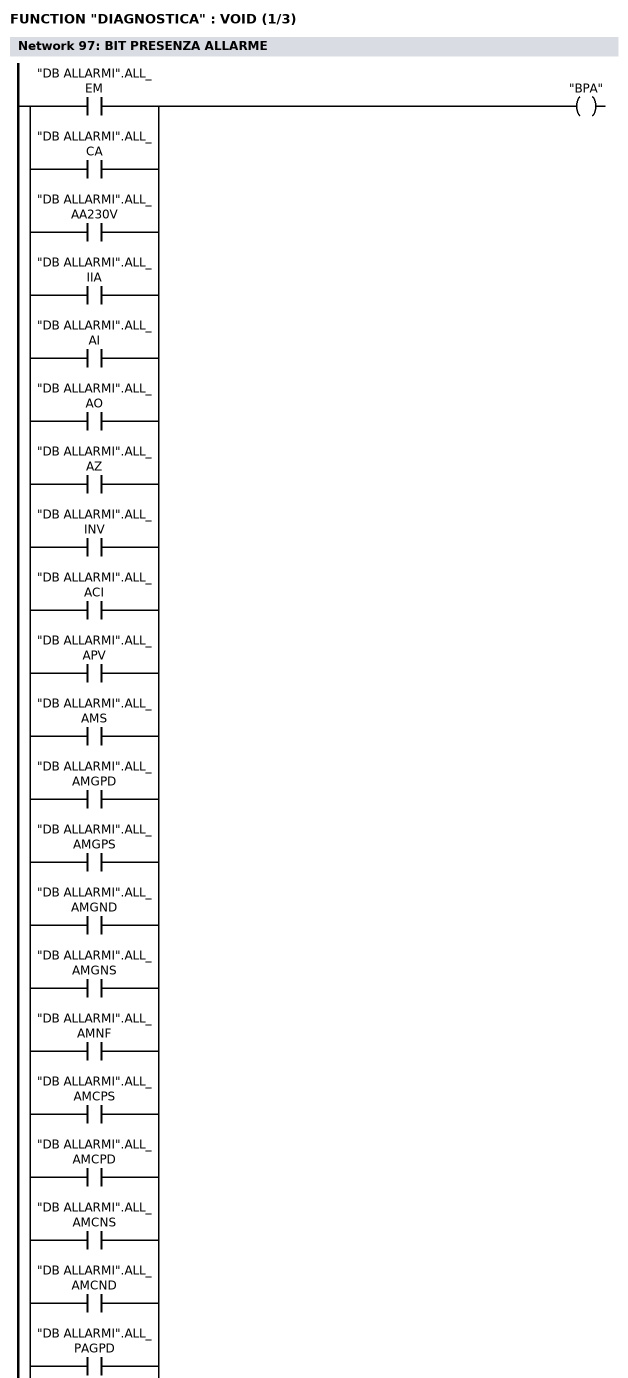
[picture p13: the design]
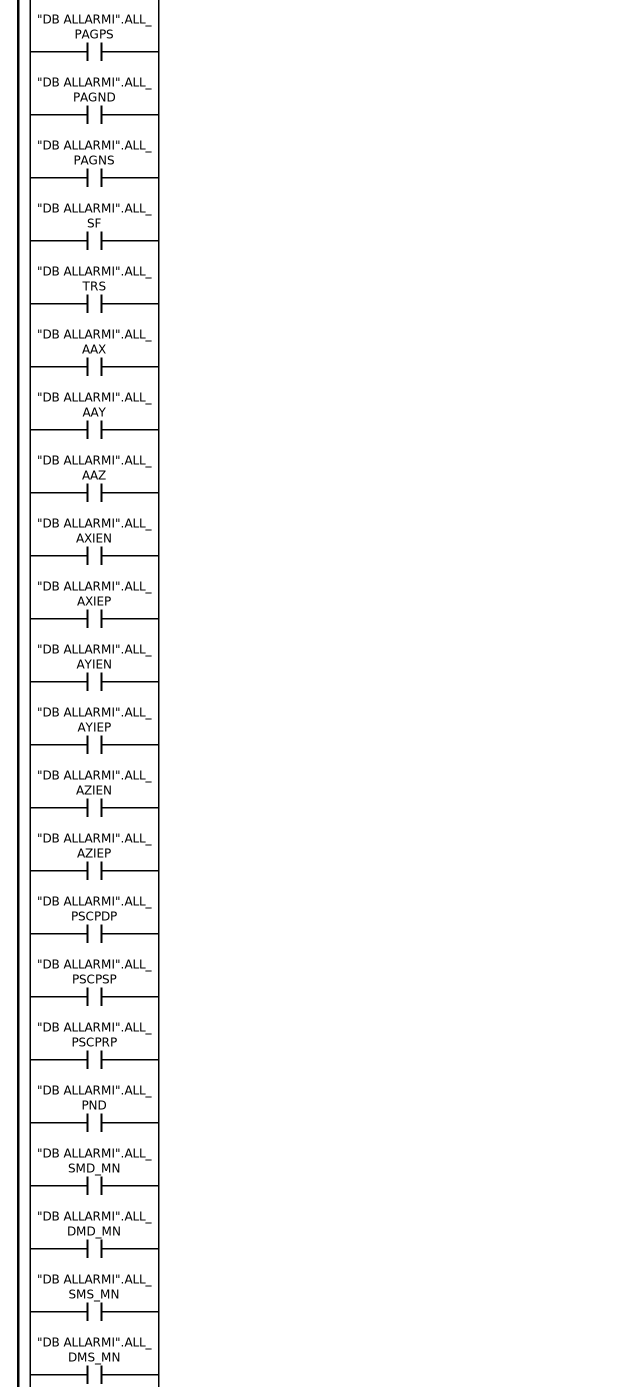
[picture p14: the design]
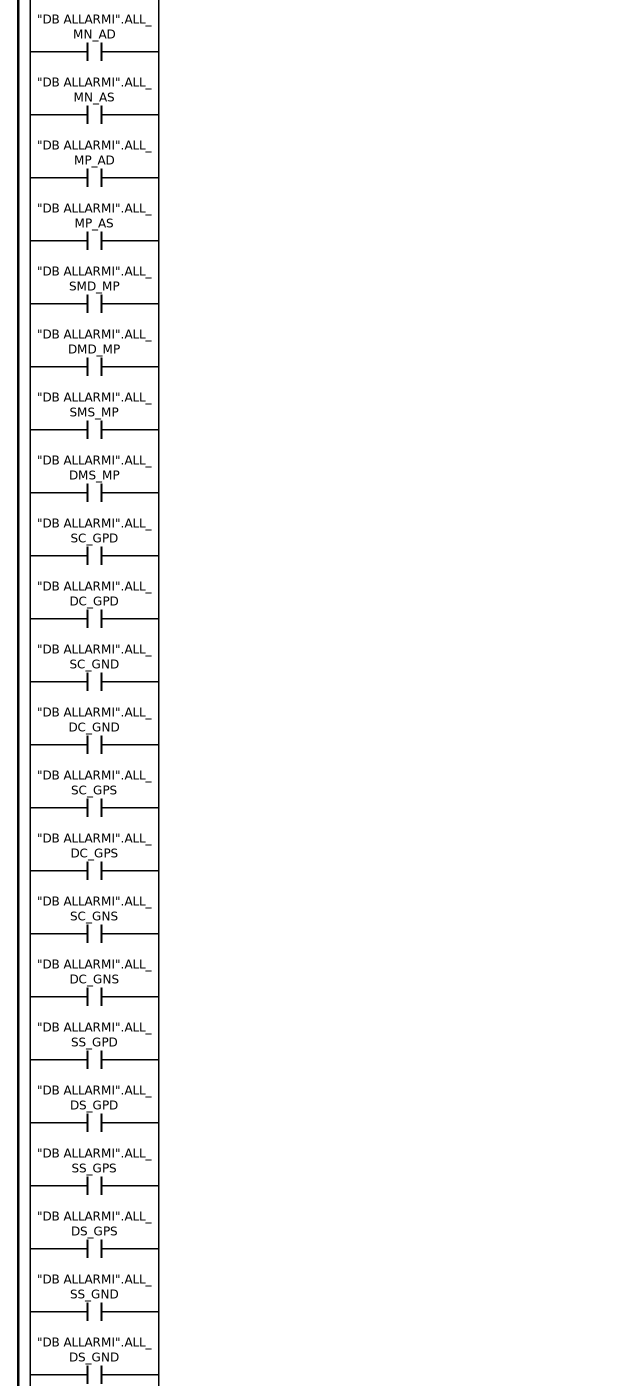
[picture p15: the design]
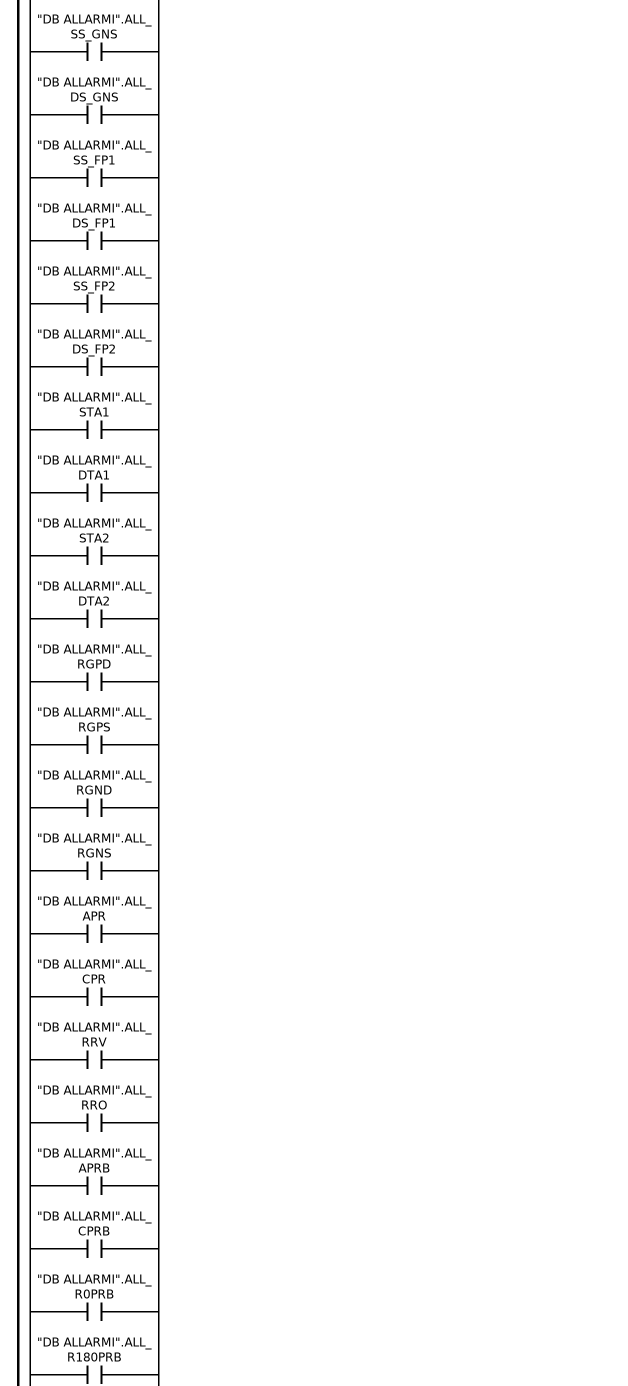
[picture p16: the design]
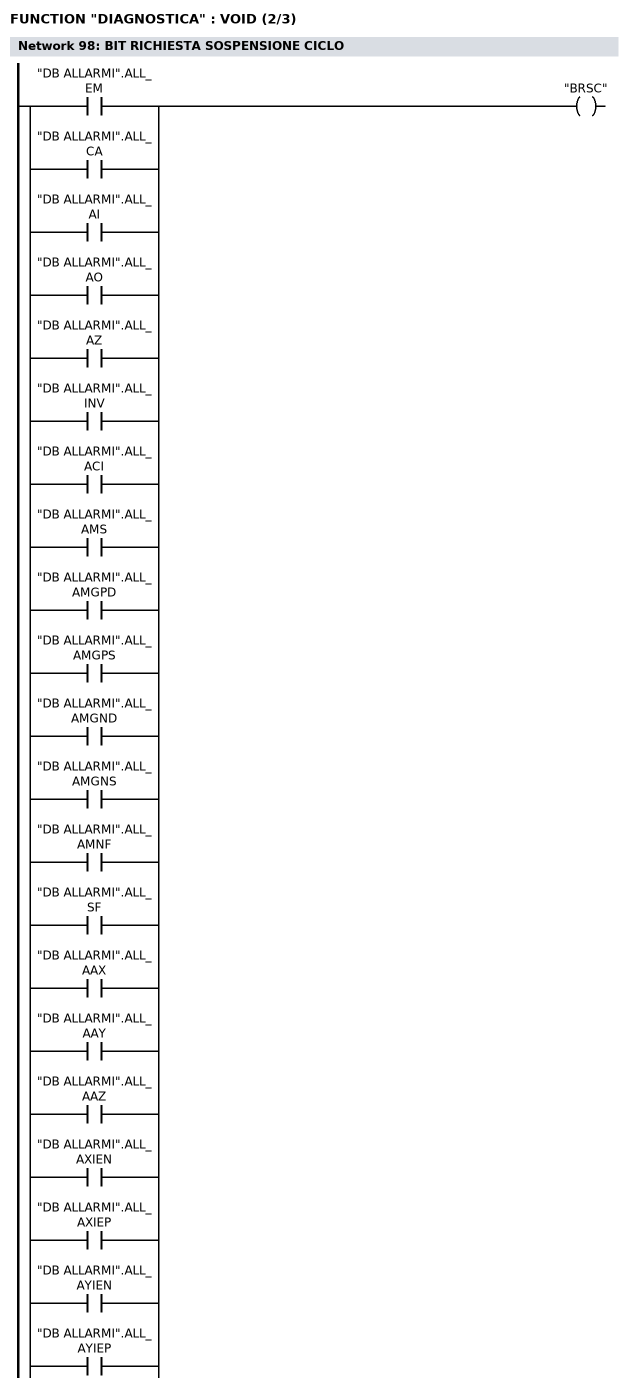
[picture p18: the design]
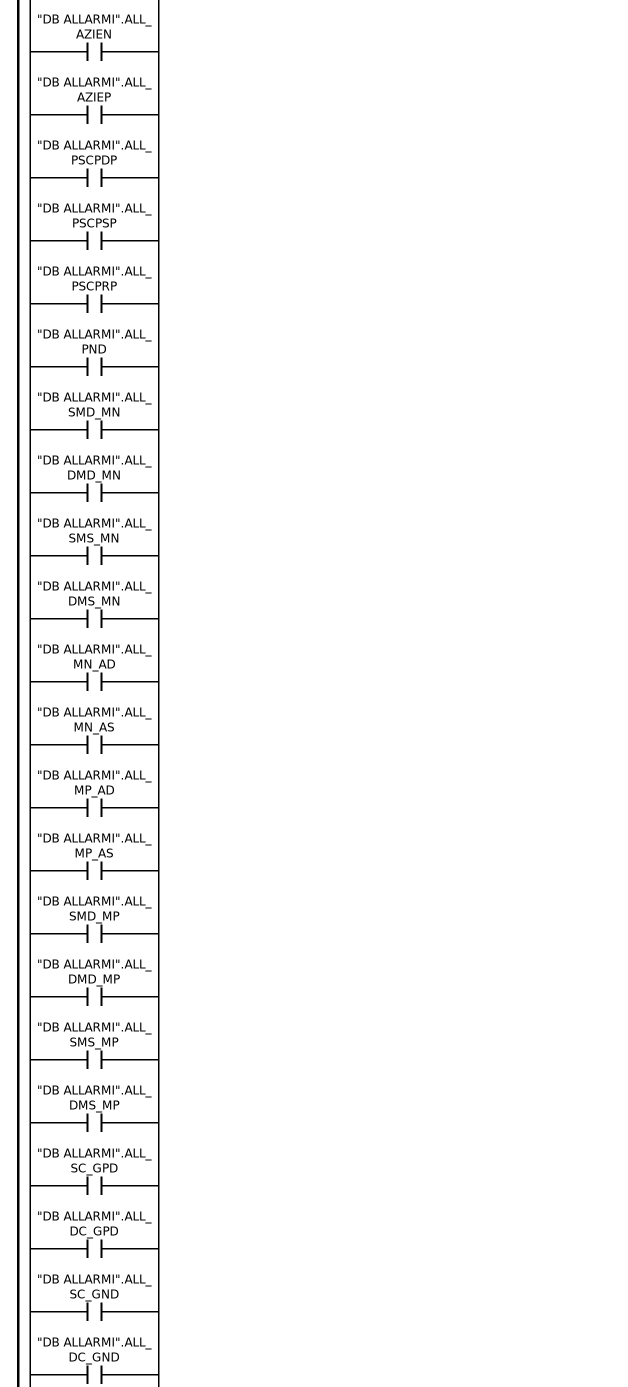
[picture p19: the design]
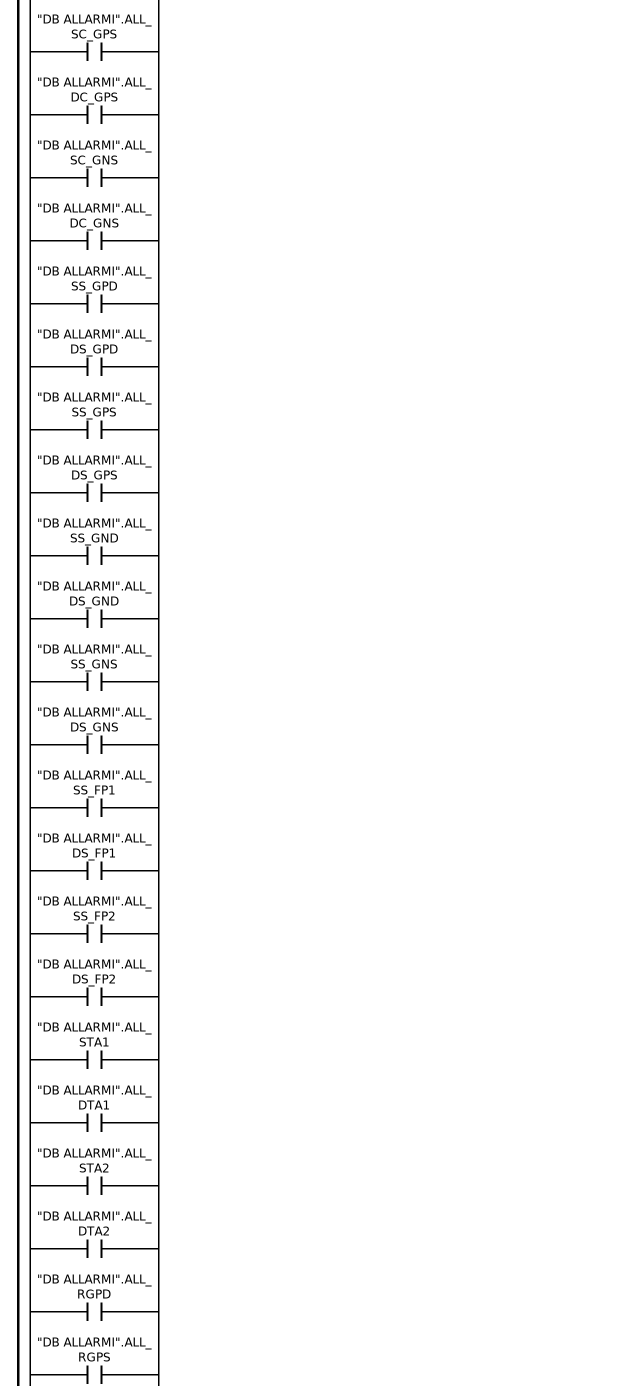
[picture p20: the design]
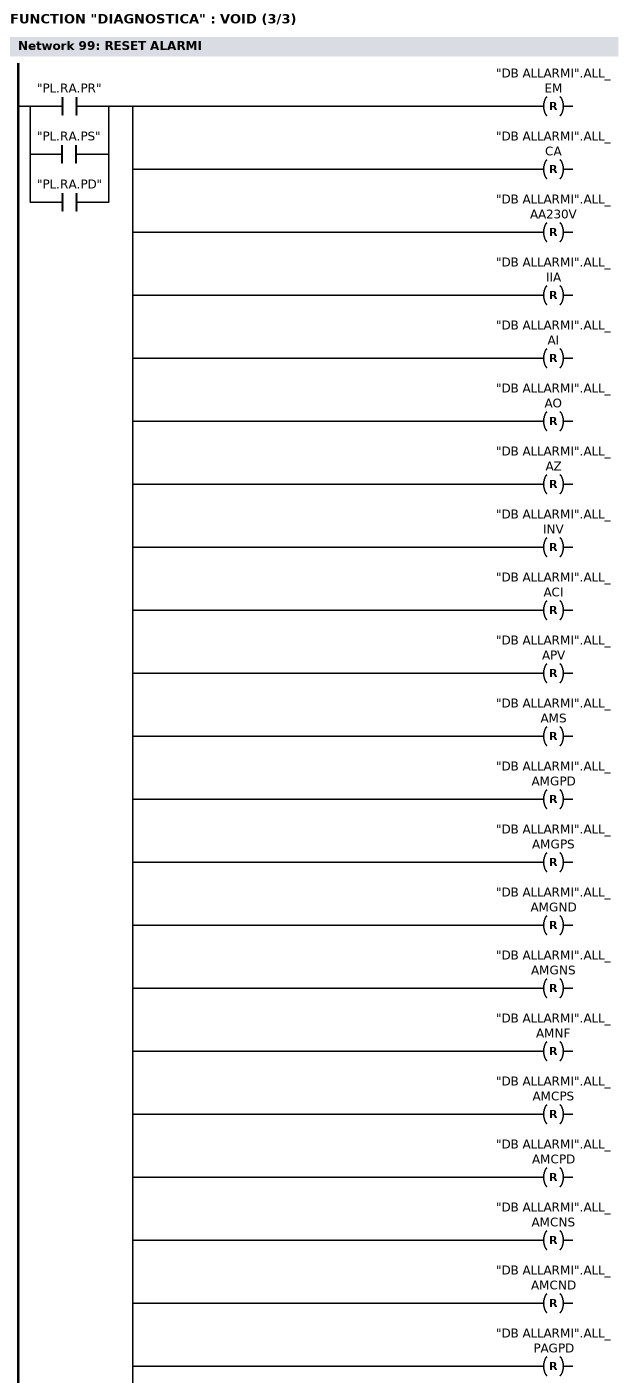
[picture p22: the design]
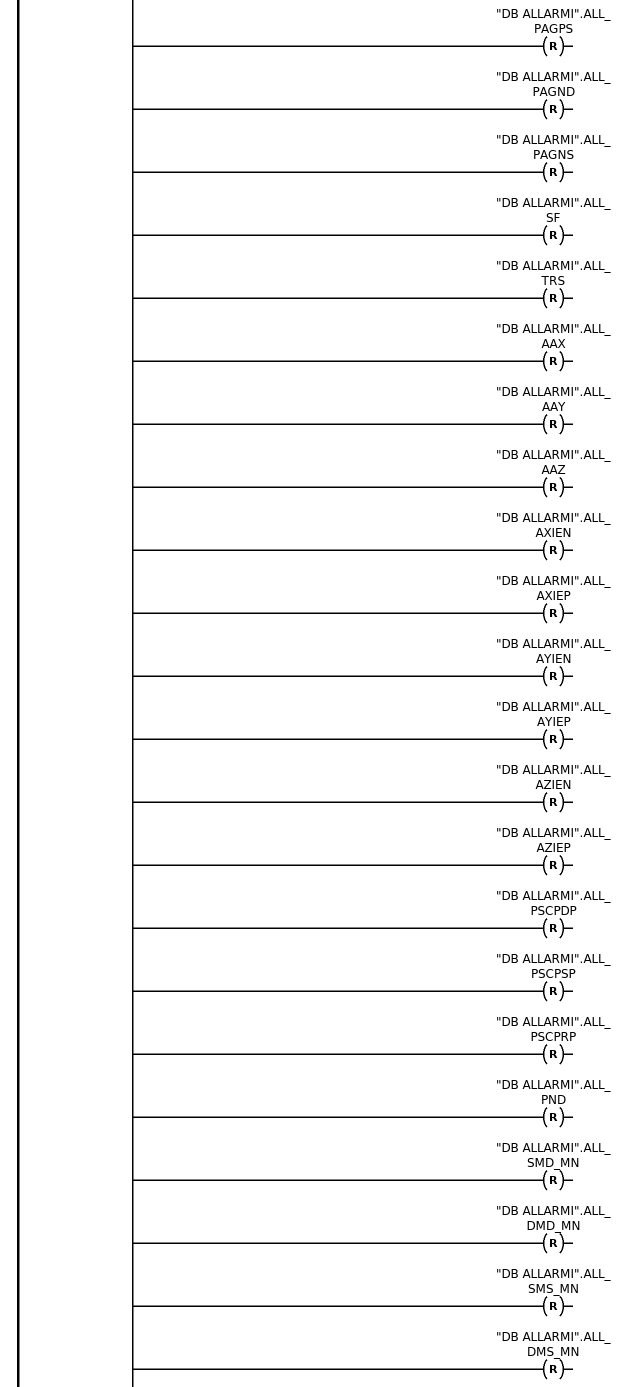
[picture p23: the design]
FUNCTION "DIAGNOSTICA" : VOID
TITLE =DIAGNOSTICA
VERSION : 0.1

BEGIN
NETWORK
TITLE =EMERGENZA

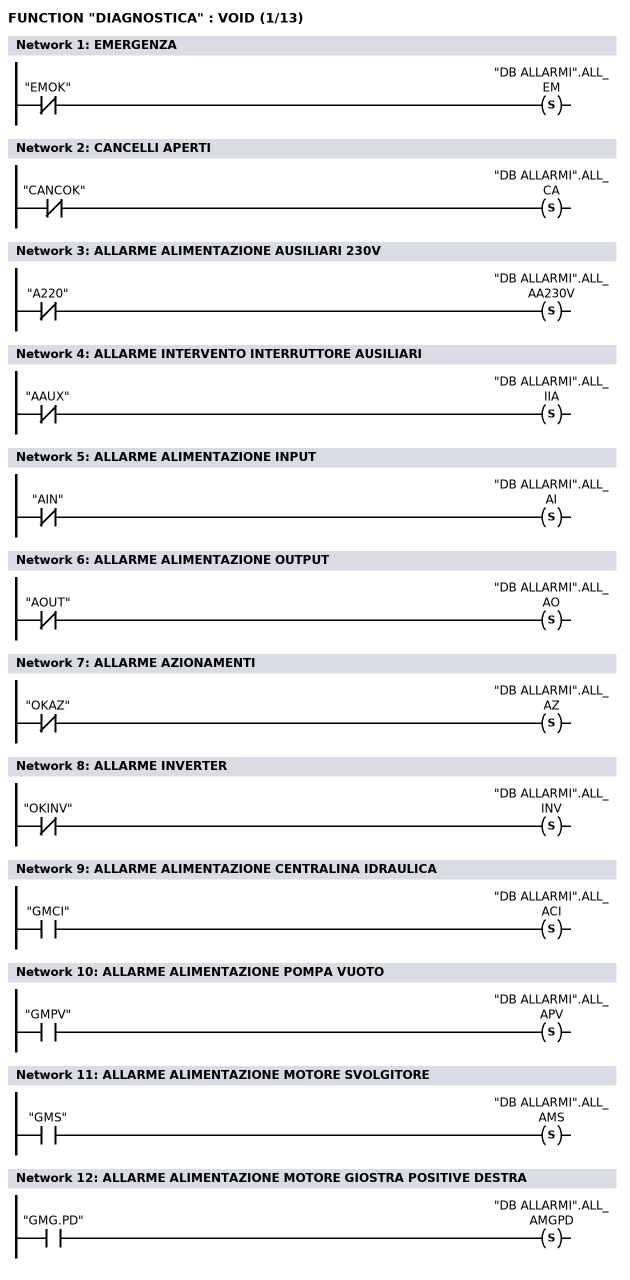
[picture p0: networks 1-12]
      UN    "EMOK";
      S     "DB ALLARMI".ALL_EM;

NETWORK
TITLE =CANCELLI APERTI

      UN    "CANCOK";
      S     "DB ALLARMI".ALL_CA;

NETWORK
TITLE =ALLARME ALIMENTAZIONE AUSILIARI 230V

      UN    "A220";
      S     "DB ALLARMI".ALL_AA230V;

NETWORK
TITLE =ALLARME INTERVENTO INTERRUTTORE AUSILIARI

      UN    "AAUX";
      S     "DB ALLARMI".ALL_IIA;

NETWORK
TITLE =ALLARME ALIMENTAZIONE INPUT

      UN    "AIN";
      S     "DB ALLARMI".ALL_AI;

NETWORK
TITLE =ALLARME ALIMENTAZIONE OUTPUT

      UN    "AOUT";
      S     "DB ALLARMI".ALL_AO;

NETWORK
TITLE =ALLARME AZIONAMENTI

      UN    "OKAZ";
      S     "DB ALLARMI".ALL_AZ;

NETWORK
TITLE =ALLARME INVERTER

      UN    "OKINV";
      S     "DB ALLARMI".ALL_INV;

NETWORK
TITLE =ALLARME ALIMENTAZIONE CENTRALINA IDRAULICA

      U     "GMCI";
      S     "DB ALLARMI".ALL_ACI;

NETWORK
TITLE =ALLARME ALIMENTAZIONE POMPA VUOTO

      U     "GMPV";
      S     "DB ALLARMI".ALL_APV;

NETWORK
TITLE =ALLARME ALIMENTAZIONE MOTORE SVOLGITORE

      U     "GMS";
      S     "DB ALLARMI".ALL_AMS;

NETWORK
TITLE =ALLARME ALIMENTAZIONE MOTORE GIOSTRA POSITIVE DESTRA

      U     "GMG.PD";
      S     "DB ALLARMI".ALL_AMGPD;

NETWORK
TITLE =ALLARME ALIMENTAZIONE MOTORE GIOSTRA POSITIVE SINISTRA

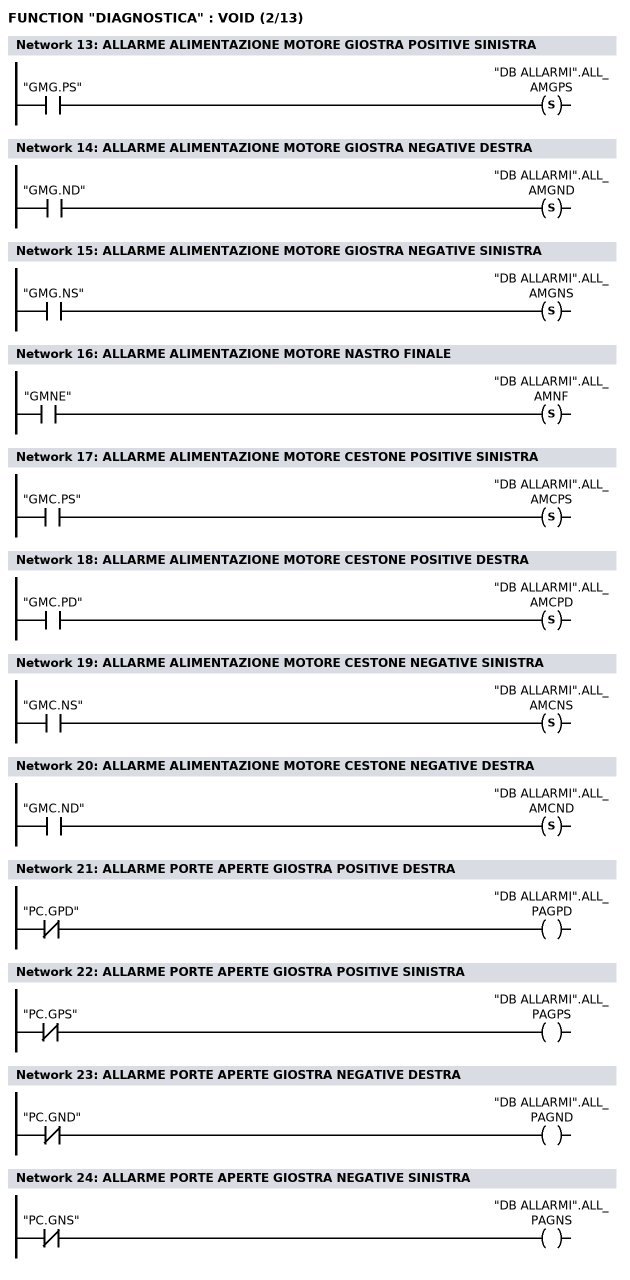
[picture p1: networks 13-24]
      U     "GMG.PS";
      S     "DB ALLARMI".ALL_AMGPS;

NETWORK
TITLE =ALLARME ALIMENTAZIONE MOTORE GIOSTRA NEGATIVE DESTRA

      U     "GMG.ND";
      S     "DB ALLARMI".ALL_AMGND;

NETWORK
TITLE =ALLARME ALIMENTAZIONE MOTORE GIOSTRA NEGATIVE SINISTRA

      U     "GMG.NS";
      S     "DB ALLARMI".ALL_AMGNS;

NETWORK
TITLE =ALLARME ALIMENTAZIONE MOTORE NASTRO FINALE

      U     "GMNE";
      S     "DB ALLARMI".ALL_AMNF;

NETWORK
TITLE =ALLARME ALIMENTAZIONE MOTORE CESTONE POSITIVE SINISTRA

      U     "GMC.PS";
      S     "DB ALLARMI".ALL_AMCPS;

NETWORK
TITLE =ALLARME ALIMENTAZIONE MOTORE CESTONE POSITIVE DESTRA

      U     "GMC.PD";
      S     "DB ALLARMI".ALL_AMCPD;

NETWORK
TITLE =ALLARME ALIMENTAZIONE MOTORE CESTONE NEGATIVE SINISTRA

      U     "GMC.NS";
      S     "DB ALLARMI".ALL_AMCNS;

NETWORK
TITLE =ALLARME ALIMENTAZIONE MOTORE CESTONE NEGATIVE DESTRA

      U     "GMC.ND";
      S     "DB ALLARMI".ALL_AMCND;

NETWORK
TITLE =ALLARME PORTE APERTE GIOSTRA POSITIVE DESTRA

      UN    "PC.GPD";
      =     "DB ALLARMI".ALL_PAGPD;

NETWORK
TITLE =ALLARME PORTE APERTE GIOSTRA POSITIVE SINISTRA

      UN    "PC.GPS";
      =     "DB ALLARMI".ALL_PAGPS;

NETWORK
TITLE =ALLARME PORTE APERTE GIOSTRA NEGATIVE DESTRA

      UN    "PC.GND";
      =     "DB ALLARMI".ALL_PAGND;

NETWORK
TITLE =ALLARME PORTE APERTE GIOSTRA NEGATIVE SINISTRA

      UN    "PC.GNS";
      =     "DB ALLARMI".ALL_PAGNS;

NETWORK
TITLE =ALLARME SEPARATORE FINITO

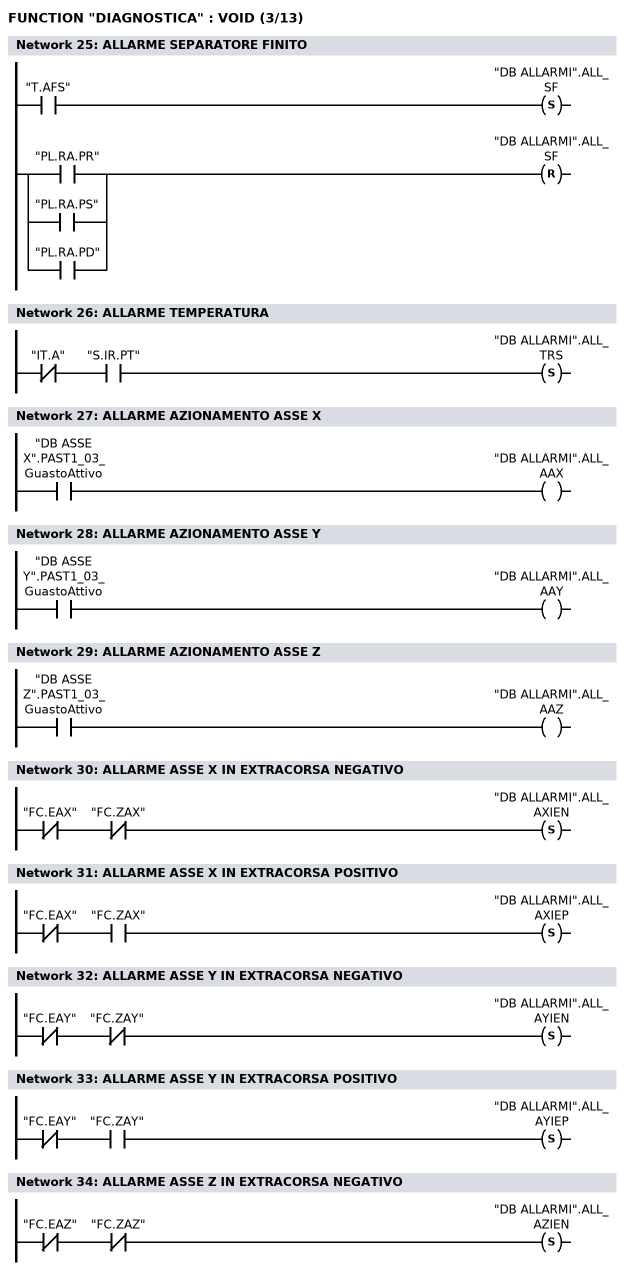
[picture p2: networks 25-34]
      U     "T.AFS";
      S     "DB ALLARMI".ALL_SF;
//----------------------------
      O     "PL.RA.PR";
      O     "PL.RA.PS";
      O     "PL.RA.PD";
      R     "DB ALLARMI".ALL_SF;

NETWORK
TITLE =ALLARME TEMPERATURA

      UN    "IT.A";
      U     "S.IR.PT";
      S     "DB ALLARMI".ALL_TRS;

NETWORK
TITLE =ALLARME AZIONAMENTO ASSE X

      U     "DB ASSE X".PAST1_03_GuastoAttivo;
      =     "DB ALLARMI".ALL_AAX;

NETWORK
TITLE =ALLARME AZIONAMENTO ASSE Y

      U     "DB ASSE Y".PAST1_03_GuastoAttivo;
      =     "DB ALLARMI".ALL_AAY;

NETWORK
TITLE =ALLARME AZIONAMENTO ASSE Z

      U     "DB ASSE Z".PAST1_03_GuastoAttivo;
      =     "DB ALLARMI".ALL_AAZ;

NETWORK
TITLE =ALLARME ASSE X IN EXTRACORSA NEGATIVO

      UN    "FC.EAX";
      UN    "FC.ZAX";
      S     "DB ALLARMI".ALL_AXIEN;

NETWORK
TITLE =ALLARME ASSE X IN EXTRACORSA POSITIVO

      UN    "FC.EAX";
      U     "FC.ZAX";
      S     "DB ALLARMI".ALL_AXIEP;

NETWORK
TITLE =ALLARME ASSE Y IN EXTRACORSA NEGATIVO

      UN    "FC.EAY";
      UN    "FC.ZAY";
      S     "DB ALLARMI".ALL_AYIEN;

NETWORK
TITLE =ALLARME ASSE Y IN EXTRACORSA POSITIVO

      UN    "FC.EAY";
      U     "FC.ZAY";
      S     "DB ALLARMI".ALL_AYIEP;

NETWORK
TITLE =ALLARME ASSE Z IN EXTRACORSA NEGATIVO

      UN    "FC.EAZ";
      UN    "FC.ZAZ";
      S     "DB ALLARMI".ALL_AZIEN;

NETWORK
TITLE =ALLARME ASSE Z IN EXTRACORSA POSITIVO

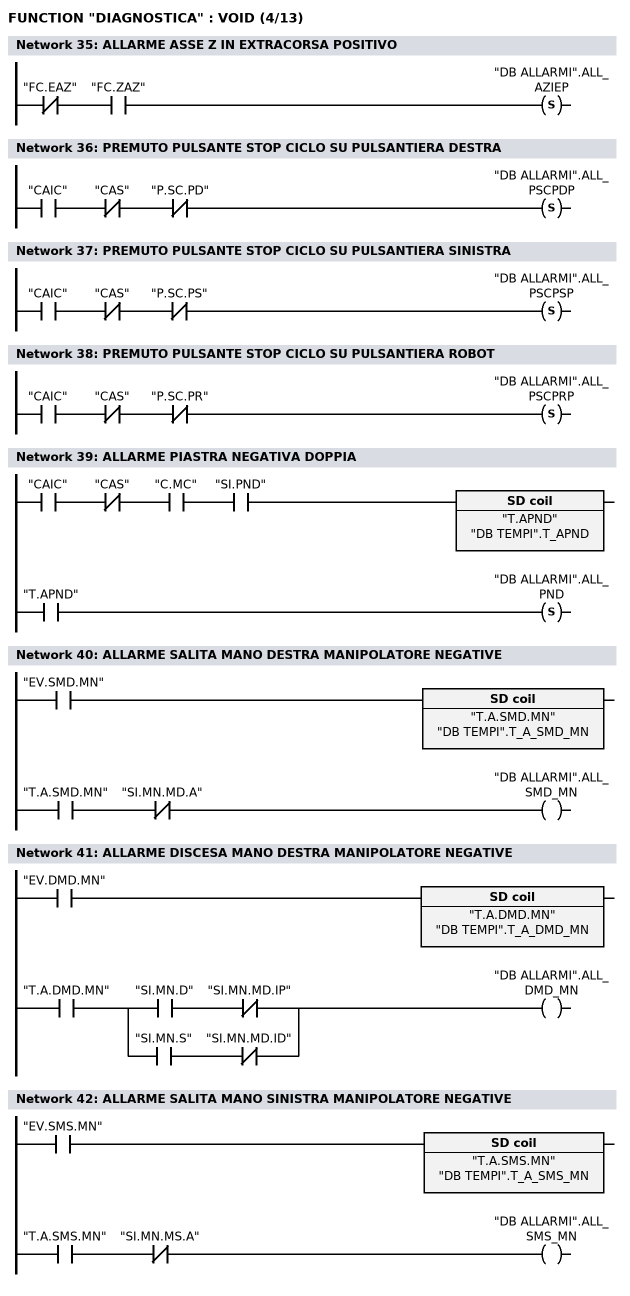
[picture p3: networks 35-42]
      UN    "FC.EAZ";
      U     "FC.ZAZ";
      S     "DB ALLARMI".ALL_AZIEP;

NETWORK
TITLE =PREMUTO PULSANTE STOP CICLO SU PULSANTIERA DESTRA

      U     "CAIC";
      UN    "CAS";
      UN    "P.SC.PD";
      S     "DB ALLARMI".ALL_PSCPDP;

NETWORK
TITLE =PREMUTO PULSANTE STOP CICLO SU PULSANTIERA SINISTRA

      U     "CAIC";
      UN    "CAS";
      UN    "P.SC.PS";
      S     "DB ALLARMI".ALL_PSCPSP;

NETWORK
TITLE =PREMUTO PULSANTE STOP CICLO SU PULSANTIERA ROBOT

      U     "CAIC";
      UN    "CAS";
      UN    "P.SC.PR";
      S     "DB ALLARMI".ALL_PSCPRP;

NETWORK
TITLE =ALLARME PIASTRA NEGATIVA DOPPIA

      U     "CAIC";
      UN    "CAS";
      U     "C.MC";
      U     "SI.PND";
      L     "DB TEMPI".T_APND;
      SE    "T.APND";
//-----------------
      U     "T.APND";
      S     "DB ALLARMI".ALL_PND;

NETWORK
TITLE =ALLARME SALITA MANO DESTRA MANIPOLATORE NEGATIVE

      U     "EV.SMD.MN";
      L     "DB TEMPI".T_A_SMD_MN;
      SE    "T.A.SMD.MN";
//---------------------------------
      U     "T.A.SMD.MN";
      UN    "SI.MN.MD.A";
      =     "DB ALLARMI".ALL_SMD_MN;

NETWORK
TITLE =ALLARME DISCESA MANO DESTRA MANIPOLATORE NEGATIVE

      U     "EV.DMD.MN";
      L     "DB TEMPI".T_A_DMD_MN;
      SE    "T.A.DMD.MN";
//---------------------------------
      U     "T.A.DMD.MN";
      U(    ;
      U     "SI.MN.D";
      UN    "SI.MN.MD.IP";
      O     ;
      U     "SI.MN.S";
      UN    "SI.MN.MD.ID";
      )     ;
      =     "DB ALLARMI".ALL_DMD_MN;

NETWORK
TITLE =ALLARME SALITA MANO SINISTRA MANIPOLATORE NEGATIVE

      U     "EV.SMS.MN";
      L     "DB TEMPI".T_A_SMS_MN;
      SE    "T.A.SMS.MN";
//---------------------------------
      U     "T.A.SMS.MN";
      UN    "SI.MN.MS.A";
      =     "DB ALLARMI".ALL_SMS_MN;

NETWORK
TITLE =ALLARME DISCESA MANO SINISTRA MANIPOLATORE NEGATIVE

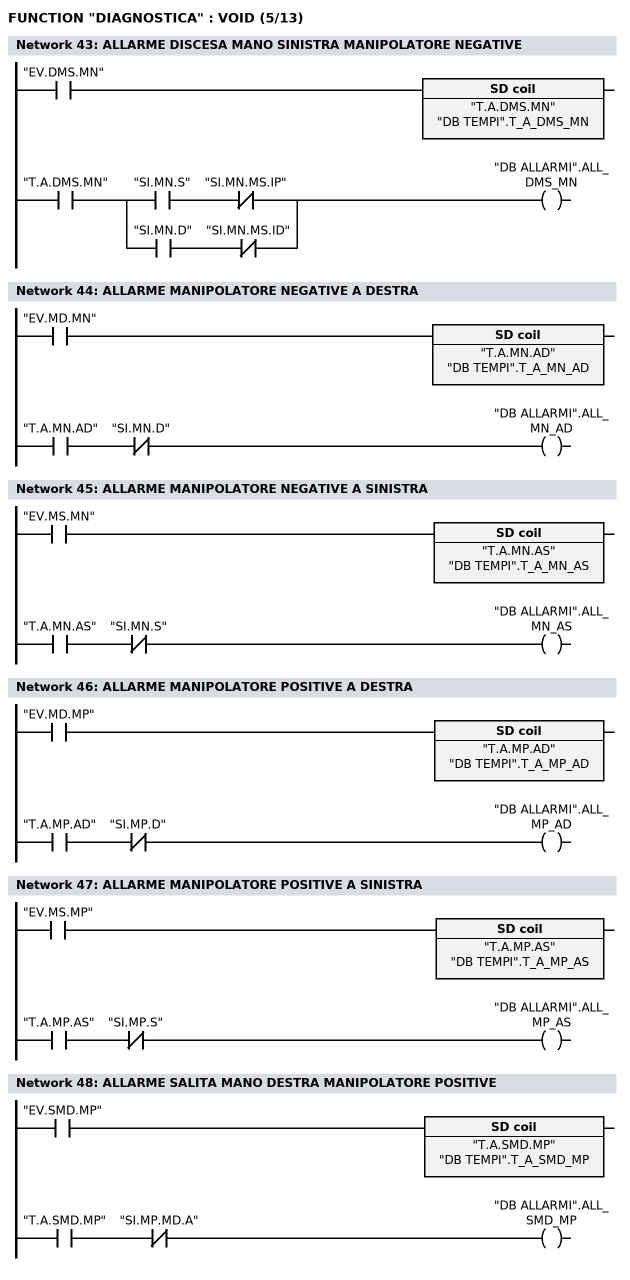
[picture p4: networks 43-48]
      U     "EV.DMS.MN";
      L     "DB TEMPI".T_A_DMS_MN;
      SE    "T.A.DMS.MN";
//---------------------------------
      U     "T.A.DMS.MN";
      U(    ;
      U     "SI.MN.S";
      UN    "SI.MN.MS.IP";
      O     ;
      U     "SI.MN.D";
      UN    "SI.MN.MS.ID";
      )     ;
      =     "DB ALLARMI".ALL_DMS_MN;

NETWORK
TITLE =ALLARME MANIPOLATORE NEGATIVE A DESTRA

      U     "EV.MD.MN";
      L     "DB TEMPI".T_A_MN_AD;
      SE    "T.A.MN.AD";
//----------------------------------
      U     "T.A.MN.AD";
      UN    "SI.MN.D";
      =     "DB ALLARMI".ALL_MN_AD;

NETWORK
TITLE =ALLARME MANIPOLATORE NEGATIVE A SINISTRA

      U     "EV.MS.MN";
      L     "DB TEMPI".T_A_MN_AS;
      SE    "T.A.MN.AS";
//----------------------------------
      U     "T.A.MN.AS";
      UN    "SI.MN.S";
      =     "DB ALLARMI".ALL_MN_AS;

NETWORK
TITLE =ALLARME MANIPOLATORE POSITIVE A DESTRA

      U     "EV.MD.MP";
      L     "DB TEMPI".T_A_MP_AD;
      SE    "T.A.MP.AD";
//----------------------------------
      U     "T.A.MP.AD";
      UN    "SI.MP.D";
      =     "DB ALLARMI".ALL_MP_AD;

NETWORK
TITLE =ALLARME MANIPOLATORE POSITIVE A SINISTRA

      U     "EV.MS.MP";
      L     "DB TEMPI".T_A_MP_AS;
      SE    "T.A.MP.AS";
//----------------------------------
      U     "T.A.MP.AS";
      UN    "SI.MP.S";
      =     "DB ALLARMI".ALL_MP_AS;

NETWORK
TITLE =ALLARME SALITA MANO DESTRA MANIPOLATORE POSITIVE

      U     "EV.SMD.MP";
      L     "DB TEMPI".T_A_SMD_MP;
      SE    "T.A.SMD.MP";
//---------------------------------
      U     "T.A.SMD.MP";
      UN    "SI.MP.MD.A";
      =     "DB ALLARMI".ALL_SMD_MP;

NETWORK
TITLE =ALLARME DISCESA MANO DESTRA MANIPOLATORE POSITIVE

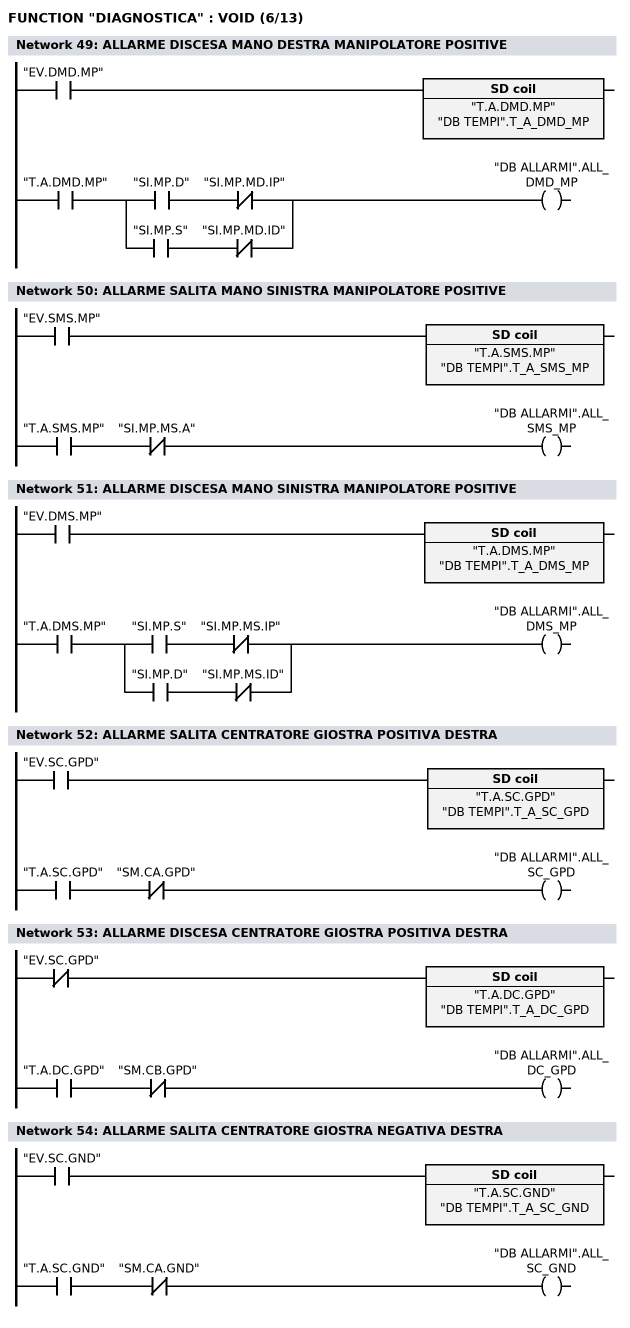
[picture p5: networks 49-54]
      U     "EV.DMD.MP";
      L     "DB TEMPI".T_A_DMD_MP;
      SE    "T.A.DMD.MP";
//---------------------------------
      U     "T.A.DMD.MP";
      U(    ;
      U     "SI.MP.D";
      UN    "SI.MP.MD.IP";
      O     ;
      U     "SI.MP.S";
      UN    "SI.MP.MD.ID";
      )     ;
      =     "DB ALLARMI".ALL_DMD_MP;

NETWORK
TITLE =ALLARME SALITA MANO SINISTRA MANIPOLATORE POSITIVE

      U     "EV.SMS.MP";
      L     "DB TEMPI".T_A_SMS_MP;
      SE    "T.A.SMS.MP";
//---------------------------------
      U     "T.A.SMS.MP";
      UN    "SI.MP.MS.A";
      =     "DB ALLARMI".ALL_SMS_MP;

NETWORK
TITLE =ALLARME DISCESA MANO SINISTRA MANIPOLATORE POSITIVE

      U     "EV.DMS.MP";
      L     "DB TEMPI".T_A_DMS_MP;
      SE    "T.A.DMS.MP";
//---------------------------------
      U     "T.A.DMS.MP";
      U(    ;
      U     "SI.MP.S";
      UN    "SI.MP.MS.IP";
      O     ;
      U     "SI.MP.D";
      UN    "SI.MP.MS.ID";
      )     ;
      =     "DB ALLARMI".ALL_DMS_MP;

NETWORK
TITLE =ALLARME SALITA CENTRATORE GIOSTRA POSITIVA DESTRA

      U     "EV.SC.GPD";
      L     "DB TEMPI".T_A_SC_GPD;
      SE    "T.A.SC.GPD";
//-----------------------------------
      U     "T.A.SC.GPD";
      UN    "SM.CA.GPD";
      =     "DB ALLARMI".ALL_SC_GPD;

NETWORK
TITLE =ALLARME DISCESA CENTRATORE GIOSTRA POSITIVA DESTRA

      UN    "EV.SC.GPD";
      L     "DB TEMPI".T_A_DC_GPD;
      SE    "T.A.DC.GPD";
//-----------------------------------
      U     "T.A.DC.GPD";
      UN    "SM.CB.GPD";
      =     "DB ALLARMI".ALL_DC_GPD;

NETWORK
TITLE =ALLARME SALITA CENTRATORE GIOSTRA NEGATIVA DESTRA

      U     "EV.SC.GND";
      L     "DB TEMPI".T_A_SC_GND;
      SE    "T.A.SC.GND";
//-----------------------------------
      U     "T.A.SC.GND";
      UN    "SM.CA.GND";
      =     "DB ALLARMI".ALL_SC_GND;

NETWORK
TITLE =ALLARME DISCESA CENTRATORE GIOSTRA NEGATIVA DESTRA

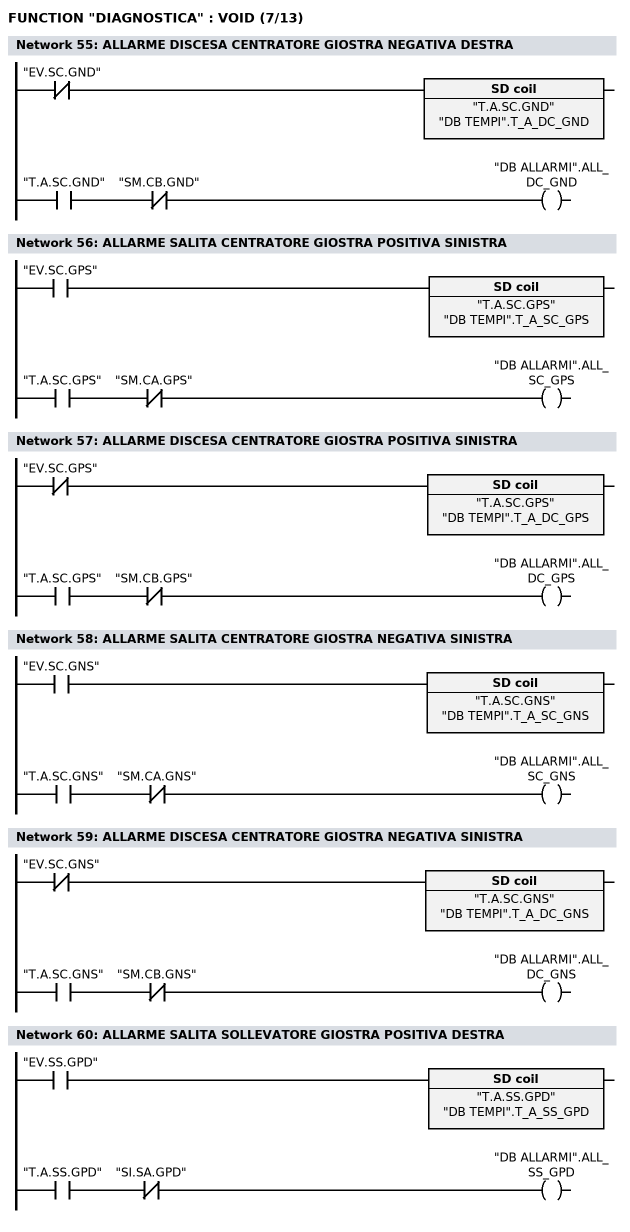
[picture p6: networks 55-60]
      UN    "EV.SC.GND";
      L     "DB TEMPI".T_A_DC_GND;
      SE    "T.A.SC.GND";
//-----------------------------------
      U     "T.A.SC.GND";
      UN    "SM.CB.GND";
      =     "DB ALLARMI".ALL_DC_GND;

NETWORK
TITLE =ALLARME SALITA CENTRATORE GIOSTRA POSITIVA SINISTRA

      U     "EV.SC.GPS";
      L     "DB TEMPI".T_A_SC_GPS;
      SE    "T.A.SC.GPS";
//-----------------------------------
      U     "T.A.SC.GPS";
      UN    "SM.CA.GPS";
      =     "DB ALLARMI".ALL_SC_GPS;

NETWORK
TITLE =ALLARME DISCESA CENTRATORE GIOSTRA POSITIVA SINISTRA

      UN    "EV.SC.GPS";
      L     "DB TEMPI".T_A_DC_GPS;
      SE    "T.A.SC.GPS";
//-----------------------------------
      U     "T.A.SC.GPS";
      UN    "SM.CB.GPS";
      =     "DB ALLARMI".ALL_DC_GPS;

NETWORK
TITLE =ALLARME SALITA CENTRATORE GIOSTRA NEGATIVA SINISTRA

      U     "EV.SC.GNS";
      L     "DB TEMPI".T_A_SC_GNS;
      SE    "T.A.SC.GNS";
//-----------------------------------
      U     "T.A.SC.GNS";
      UN    "SM.CA.GNS";
      =     "DB ALLARMI".ALL_SC_GNS;

NETWORK
TITLE =ALLARME DISCESA CENTRATORE GIOSTRA NEGATIVA SINISTRA

      UN    "EV.SC.GNS";
      L     "DB TEMPI".T_A_DC_GNS;
      SE    "T.A.SC.GNS";
//-----------------------------------
      U     "T.A.SC.GNS";
      UN    "SM.CB.GNS";
      =     "DB ALLARMI".ALL_DC_GNS;

NETWORK
TITLE =ALLARME SALITA SOLLEVATORE GIOSTRA POSITIVA DESTRA

      U     "EV.SS.GPD";
      L     "DB TEMPI".T_A_SS_GPD;
      SE    "T.A.SS.GPD";
//-----------------------------------
      U     "T.A.SS.GPD";
      UN    "SI.SA.GPD";
      =     "DB ALLARMI".ALL_SS_GPD;

NETWORK
TITLE =ALLARME DISCESA SOLLEVATORE GIOSTRA POSITIVA DESTRA

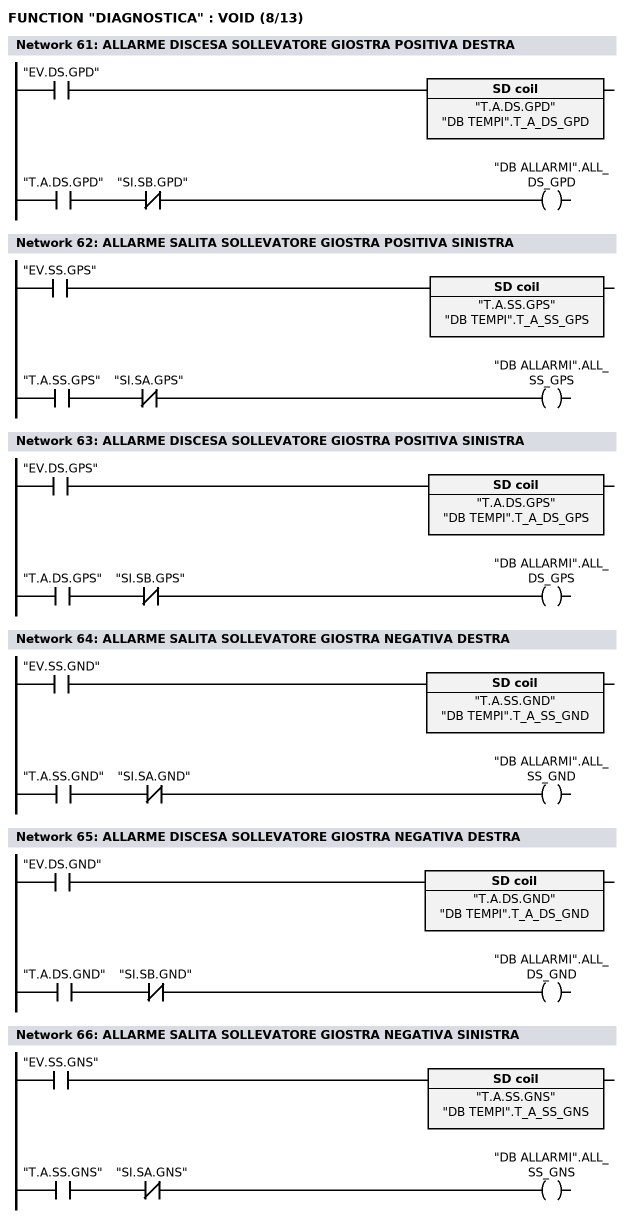
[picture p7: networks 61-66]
      U     "EV.DS.GPD";
      L     "DB TEMPI".T_A_DS_GPD;
      SE    "T.A.DS.GPD";
//-----------------------------------
      U     "T.A.DS.GPD";
      UN    "SI.SB.GPD";
      =     "DB ALLARMI".ALL_DS_GPD;

NETWORK
TITLE =ALLARME SALITA SOLLEVATORE GIOSTRA POSITIVA SINISTRA

      U     "EV.SS.GPS";
      L     "DB TEMPI".T_A_SS_GPS;
      SE    "T.A.SS.GPS";
//-----------------------------------
      U     "T.A.SS.GPS";
      UN    "SI.SA.GPS";
      =     "DB ALLARMI".ALL_SS_GPS;

NETWORK
TITLE =ALLARME DISCESA SOLLEVATORE GIOSTRA POSITIVA SINISTRA

      U     "EV.DS.GPS";
      L     "DB TEMPI".T_A_DS_GPS;
      SE    "T.A.DS.GPS";
//-----------------------------------
      U     "T.A.DS.GPS";
      UN    "SI.SB.GPS";
      =     "DB ALLARMI".ALL_DS_GPS;

NETWORK
TITLE =ALLARME SALITA SOLLEVATORE GIOSTRA NEGATIVA DESTRA

      U     "EV.SS.GND";
      L     "DB TEMPI".T_A_SS_GND;
      SE    "T.A.SS.GND";
//-----------------------------------
      U     "T.A.SS.GND";
      UN    "SI.SA.GND";
      =     "DB ALLARMI".ALL_SS_GND;

NETWORK
TITLE =ALLARME DISCESA SOLLEVATORE GIOSTRA NEGATIVA DESTRA

      U     "EV.DS.GND";
      L     "DB TEMPI".T_A_DS_GND;
      SE    "T.A.DS.GND";
//-----------------------------------
      U     "T.A.DS.GND";
      UN    "SI.SB.GND";
      =     "DB ALLARMI".ALL_DS_GND;

NETWORK
TITLE =ALLARME SALITA SOLLEVATORE GIOSTRA NEGATIVA SINISTRA

      U     "EV.SS.GNS";
      L     "DB TEMPI".T_A_SS_GNS;
      SE    "T.A.SS.GNS";
//-----------------------------------
      U     "T.A.SS.GNS";
      UN    "SI.SA.GNS";
      =     "DB ALLARMI".ALL_SS_GNS;

NETWORK
TITLE =ALLARME DISCESA SOLLEVATORE GIOSTRA NEGATIVA SINISTRA

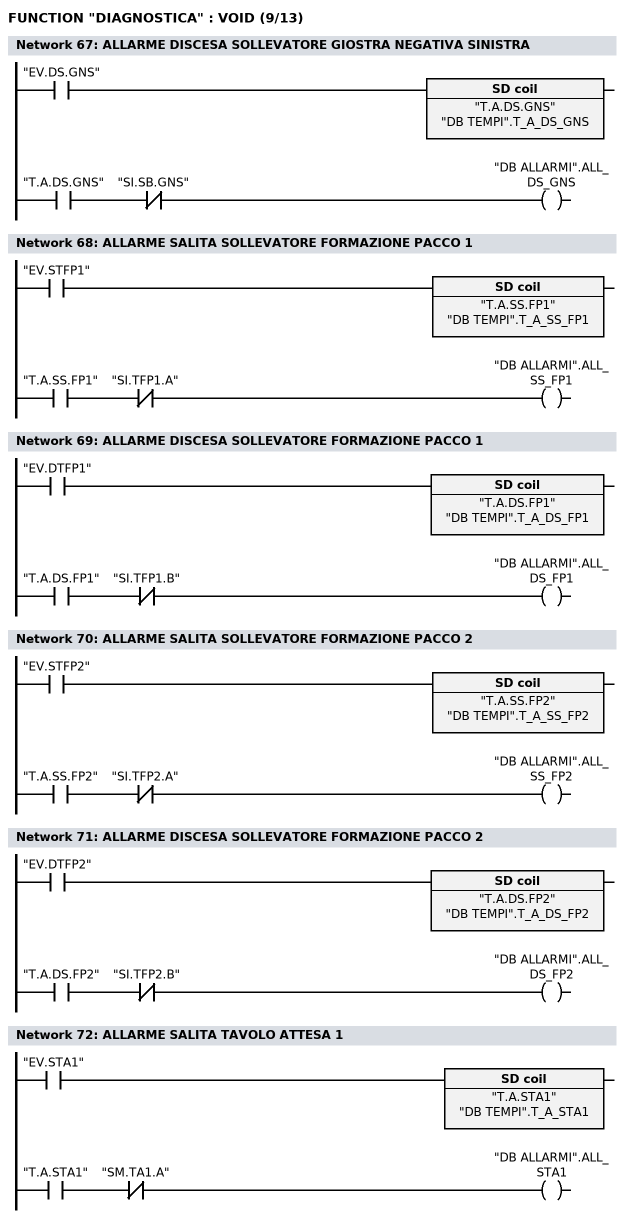
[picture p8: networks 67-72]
      U     "EV.DS.GNS";
      L     "DB TEMPI".T_A_DS_GNS;
      SE    "T.A.DS.GNS";
//-----------------------------------
      U     "T.A.DS.GNS";
      UN    "SI.SB.GNS";
      =     "DB ALLARMI".ALL_DS_GNS;

NETWORK
TITLE =ALLARME SALITA SOLLEVATORE FORMAZIONE PACCO 1

      U     "EV.STFP1";
      L     "DB TEMPI".T_A_SS_FP1;
      SE    "T.A.SS.FP1";
//-----------------------------------
      U     "T.A.SS.FP1";
      UN    "SI.TFP1.A";
      =     "DB ALLARMI".ALL_SS_FP1;

NETWORK
TITLE =ALLARME DISCESA SOLLEVATORE FORMAZIONE PACCO 1

      U     "EV.DTFP1";
      L     "DB TEMPI".T_A_DS_FP1;
      SE    "T.A.DS.FP1";
//-----------------------------------
      U     "T.A.DS.FP1";
      UN    "SI.TFP1.B";
      =     "DB ALLARMI".ALL_DS_FP1;

NETWORK
TITLE =ALLARME SALITA SOLLEVATORE FORMAZIONE PACCO 2

      U     "EV.STFP2";
      L     "DB TEMPI".T_A_SS_FP2;
      SE    "T.A.SS.FP2";
//-----------------------------------
      U     "T.A.SS.FP2";
      UN    "SI.TFP2.A";
      =     "DB ALLARMI".ALL_SS_FP2;

NETWORK
TITLE =ALLARME DISCESA SOLLEVATORE FORMAZIONE PACCO 2

      U     "EV.DTFP2";
      L     "DB TEMPI".T_A_DS_FP2;
      SE    "T.A.DS.FP2";
//-----------------------------------
      U     "T.A.DS.FP2";
      UN    "SI.TFP2.B";
      =     "DB ALLARMI".ALL_DS_FP2;

NETWORK
TITLE =ALLARME SALITA TAVOLO ATTESA 1

      U     "EV.STA1";
      L     "DB TEMPI".T_A_STA1;
      SE    "T.A.STA1";
//-----------------------------------
      U     "T.A.STA1";
      UN    "SM.TA1.A";
      =     "DB ALLARMI".ALL_STA1;

NETWORK
TITLE =ALLARME DISCESA TAVOLO ATTESA 1

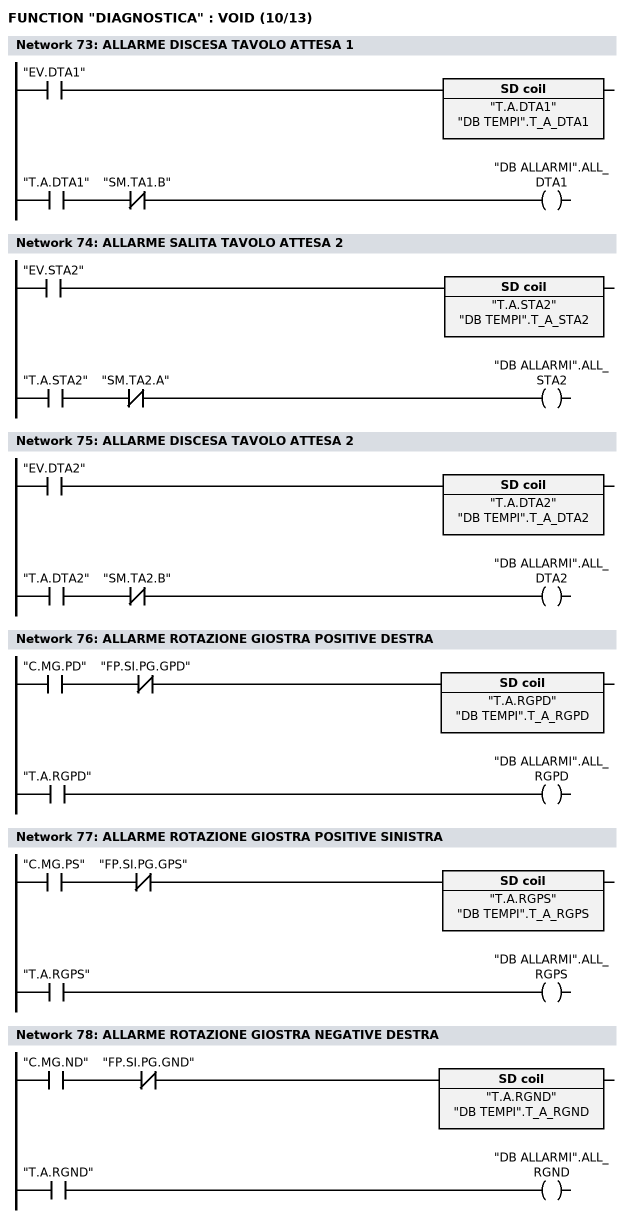
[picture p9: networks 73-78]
      U     "EV.DTA1";
      L     "DB TEMPI".T_A_DTA1;
      SE    "T.A.DTA1";
//-----------------------------------
      U     "T.A.DTA1";
      UN    "SM.TA1.B";
      =     "DB ALLARMI".ALL_DTA1;

NETWORK
TITLE =ALLARME SALITA TAVOLO ATTESA 2

      U     "EV.STA2";
      L     "DB TEMPI".T_A_STA2;
      SE    "T.A.STA2";
//-----------------------------------
      U     "T.A.STA2";
      UN    "SM.TA2.A";
      =     "DB ALLARMI".ALL_STA2;

NETWORK
TITLE =ALLARME DISCESA TAVOLO ATTESA 2

      U     "EV.DTA2";
      L     "DB TEMPI".T_A_DTA2;
      SE    "T.A.DTA2";
//-----------------------------------
      U     "T.A.DTA2";
      UN    "SM.TA2.B";
      =     "DB ALLARMI".ALL_DTA2;

NETWORK
TITLE =ALLARME ROTAZIONE GIOSTRA POSITIVE DESTRA

      U     "C.MG.PD";
      UN    "FP.SI.PG.GPD";
      L     "DB TEMPI".T_A_RGPD;
      SE    "T.A.RGPD";
//------------------------------------
      U     "T.A.RGPD";
      =     "DB ALLARMI".ALL_RGPD;

NETWORK
TITLE =ALLARME ROTAZIONE GIOSTRA POSITIVE SINISTRA

      U     "C.MG.PS";
      UN    "FP.SI.PG.GPS";
      L     "DB TEMPI".T_A_RGPS;
      SE    "T.A.RGPS";
//------------------------------------
      U     "T.A.RGPS";
      =     "DB ALLARMI".ALL_RGPS;

NETWORK
TITLE =ALLARME ROTAZIONE GIOSTRA NEGATIVE DESTRA

      U     "C.MG.ND";
      UN    "FP.SI.PG.GND";
      L     "DB TEMPI".T_A_RGND;
      SE    "T.A.RGND";
//------------------------------------
      U     "T.A.RGND";
      =     "DB ALLARMI".ALL_RGND;

NETWORK
TITLE =ALLARME ROTAZIONE GIOSTRA NEGATIVE SINISTRA

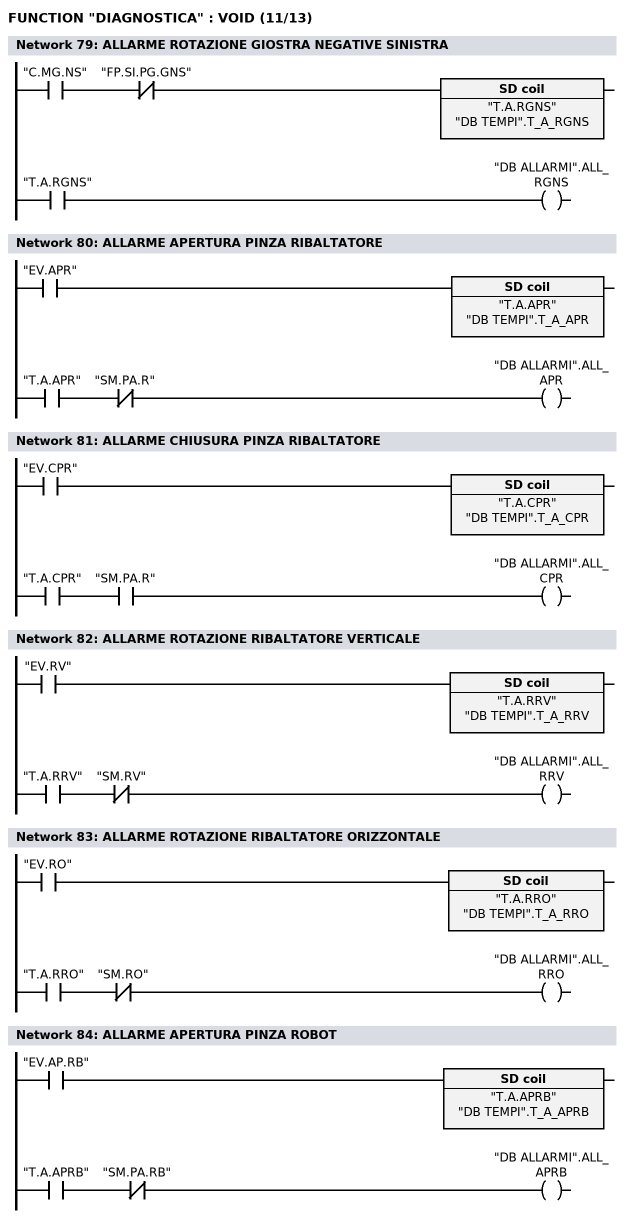
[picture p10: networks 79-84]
      U     "C.MG.NS";
      UN    "FP.SI.PG.GNS";
      L     "DB TEMPI".T_A_RGNS;
      SE    "T.A.RGNS";
//------------------------------------
      U     "T.A.RGNS";
      =     "DB ALLARMI".ALL_RGNS;

NETWORK
TITLE =ALLARME APERTURA PINZA RIBALTATORE

      U     "EV.APR";
      L     "DB TEMPI".T_A_APR;
      SE    "T.A.APR";
//------------------------------------
      U     "T.A.APR";
      UN    "SM.PA.R";
      =     "DB ALLARMI".ALL_APR;

NETWORK
TITLE =ALLARME CHIUSURA PINZA RIBALTATORE

      U     "EV.CPR";
      L     "DB TEMPI".T_A_CPR;
      SE    "T.A.CPR";
//------------------------------------
      U     "T.A.CPR";
      U     "SM.PA.R";
      =     "DB ALLARMI".ALL_CPR;

NETWORK
TITLE =ALLARME ROTAZIONE RIBALTATORE VERTICALE

      U     "EV.RV";
      L     "DB TEMPI".T_A_RRV;
      SE    "T.A.RRV";
//-------------------------------------
      U     "T.A.RRV";
      UN    "SM.RV";
      =     "DB ALLARMI".ALL_RRV;

NETWORK
TITLE =ALLARME ROTAZIONE RIBALTATORE ORIZZONTALE

      U     "EV.RO";
      L     "DB TEMPI".T_A_RRO;
      SE    "T.A.RRO";
//-------------------------------------
      U     "T.A.RRO";
      UN    "SM.RO";
      =     "DB ALLARMI".ALL_RRO;

NETWORK
TITLE =ALLARME APERTURA PINZA ROBOT

      U     "EV.AP.RB";
      L     "DB TEMPI".T_A_APRB;
      SE    "T.A.APRB";
//--------------------------------------
      U     "T.A.APRB";
      UN    "SM.PA.RB";
      =     "DB ALLARMI".ALL_APRB;

NETWORK
TITLE =ALLARME CHIUSURA PINZA ROBOT

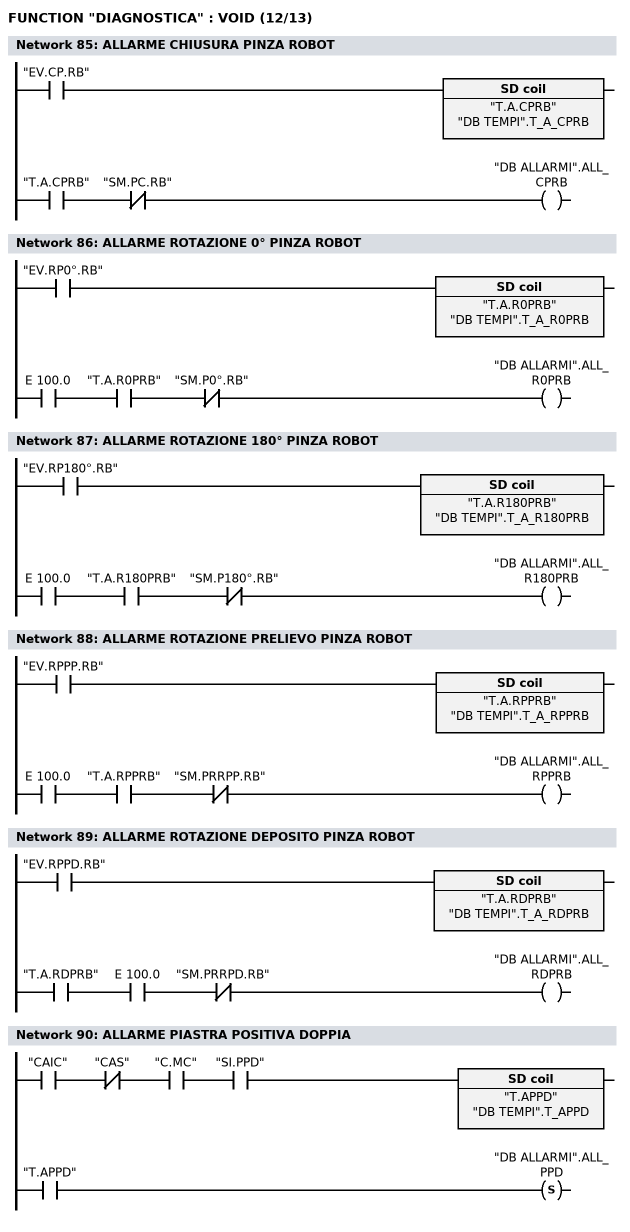
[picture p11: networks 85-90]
      U     "EV.CP.RB";
      L     "DB TEMPI".T_A_CPRB;
      SE    "T.A.CPRB";
//--------------------------------------
      U     "T.A.CPRB";
      UN    "SM.PC.RB";
      =     "DB ALLARMI".ALL_CPRB;

NETWORK
TITLE =ALLARME ROTAZIONE 0° PINZA ROBOT

      U     "EV.RP0°.RB";
      L     "DB TEMPI".T_A_R0PRB;
      SE    "T.A.R0PRB";
//--------------------------------------
      U     E    100.0;
      U     "T.A.R0PRB";
      UN    "SM.P0°.RB";

      =     "DB ALLARMI".ALL_R0PRB;
NETWORK
TITLE =ALLARME ROTAZIONE 180° PINZA ROBOT

      U     "EV.RP180°.RB";
      L     "DB TEMPI".T_A_R180PRB;
      SE    "T.A.R180PRB";
//--------------------------------------
      U     E    100.0;
      U     "T.A.R180PRB";
      UN    "SM.P180°.RB";

      =     "DB ALLARMI".ALL_R180PRB;
NETWORK
TITLE =ALLARME ROTAZIONE PRELIEVO PINZA ROBOT

      U     "EV.RPPP.RB";
      L     "DB TEMPI".T_A_RPPRB;
      SE    "T.A.RPPRB";
//---------------------------------------
      U     E    100.0;
      U     "T.A.RPPRB";
      UN    "SM.PRRPP.RB";

      =     "DB ALLARMI".ALL_RPPRB;
NETWORK
TITLE =ALLARME ROTAZIONE DEPOSITO PINZA ROBOT

      U     "EV.RPPD.RB";
      L     "DB TEMPI".T_A_RDPRB;
      SE    "T.A.RDPRB";
//---------------------------------------
      U     "T.A.RDPRB";
      U     E    100.0;
      UN    "SM.PRRPD.RB";

      =     "DB ALLARMI".ALL_RDPRB;
NETWORK
TITLE =ALLARME PIASTRA POSITIVA DOPPIA

      U     "CAIC";
      UN    "CAS";
      U     "C.MC";
      U     "SI.PPD";
      L     "DB TEMPI".T_APPD;
      SE    "T.APPD";
//-----------------
      U     "T.APPD";
      S     "DB ALLARMI".ALL_PPD;

NETWORK
TITLE =

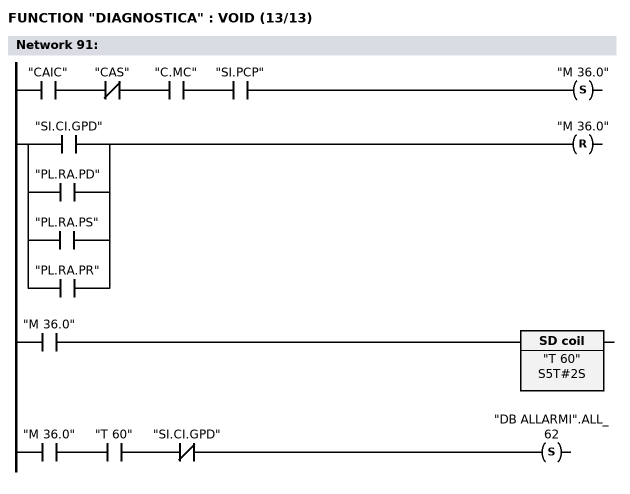
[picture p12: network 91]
      U     "CAIC";
      UN    "CAS";

      U     "C.MC";
      U     "SI.PCP";
      S     "M      36.0";
      O     "SI.CI.GPD";
      O     "PL.RA.PD";
      O     "PL.RA.PS";
      O     "PL.RA.PR";
      R     "M      36.0";
      U     "M      36.0";
      L     S5T#2S;
      SE    "T      60";
      U     "M      36.0";
      U     "T      60";
      UN    "SI.CI.GPD";
      S     "DB ALLARMI".ALL_62;
NETWORK
TITLE =

      CLR   ;
      =     "DB ALLARMI".ALL_63;

NETWORK
TITLE =

      CLR   ;
      =     "DB ALLARMI".ALL_64;

NETWORK
TITLE =

      CLR   ;
      =     "DB ALLARMI".ALL_65;

NETWORK
TITLE =

      CLR   ;
      =     "DB ALLARMI".ALL_66;

NETWORK
TITLE =

      CLR   ;
      =     "DB ALLARMI".ALL_67;

NETWORK
TITLE =BIT PRESENZA ALLARME

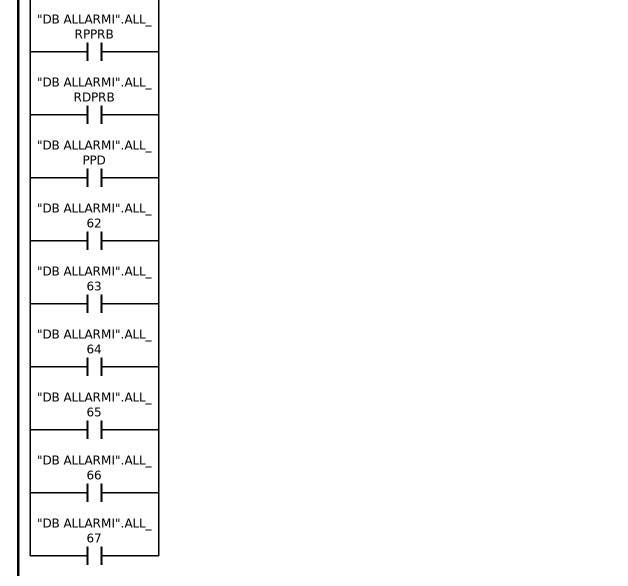
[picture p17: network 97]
      O     "DB ALLARMI".ALL_EM;
      O     "DB ALLARMI".ALL_CA;
      O     "DB ALLARMI".ALL_AA230V;
      O     "DB ALLARMI".ALL_IIA;
      O     "DB ALLARMI".ALL_AI;
      O     "DB ALLARMI".ALL_AO;
      O     "DB ALLARMI".ALL_AZ;
      O     "DB ALLARMI".ALL_INV;
      O     "DB ALLARMI".ALL_ACI;
      O     "DB ALLARMI".ALL_APV;
      O     "DB ALLARMI".ALL_AMS;
      O     "DB ALLARMI".ALL_AMGPD;
      O     "DB ALLARMI".ALL_AMGPS;
      O     "DB ALLARMI".ALL_AMGND;
      O     "DB ALLARMI".ALL_AMGNS;
      O     "DB ALLARMI".ALL_AMNF;
      O     "DB ALLARMI".ALL_AMCPS;
      O     "DB ALLARMI".ALL_AMCPD;
      O     "DB ALLARMI".ALL_AMCNS;
      O     "DB ALLARMI".ALL_AMCND;
      O     "DB ALLARMI".ALL_PAGPD;
      O     "DB ALLARMI".ALL_PAGPS;
      O     "DB ALLARMI".ALL_PAGND;
      O     "DB ALLARMI".ALL_PAGNS;
      O     "DB ALLARMI".ALL_SF;
      O     "DB ALLARMI".ALL_TRS;
      O     "DB ALLARMI".ALL_AAX;
      O     "DB ALLARMI".ALL_AAY;
      O     "DB ALLARMI".ALL_AAZ;
      O     "DB ALLARMI".ALL_AXIEN;
      O     "DB ALLARMI".ALL_AXIEP;
      O     "DB ALLARMI".ALL_AYIEN;
      O     "DB ALLARMI".ALL_AYIEP;
      O     "DB ALLARMI".ALL_AZIEN;
      O     "DB ALLARMI".ALL_AZIEP;
      O     "DB ALLARMI".ALL_PSCPDP;
      O     "DB ALLARMI".ALL_PSCPSP;
      O     "DB ALLARMI".ALL_PSCPRP;
      O     "DB ALLARMI".ALL_PND;
      O     "DB ALLARMI".ALL_SMD_MN;
      O     "DB ALLARMI".ALL_DMD_MN;
      O     "DB ALLARMI".ALL_SMS_MN;
      O     "DB ALLARMI".ALL_DMS_MN;
      O     "DB ALLARMI".ALL_MN_AD;
      O     "DB ALLARMI".ALL_MN_AS;
      O     "DB ALLARMI".ALL_MP_AD;
      O     "DB ALLARMI".ALL_MP_AS;
      O     "DB ALLARMI".ALL_SMD_MP;
      O     "DB ALLARMI".ALL_DMD_MP;
      O     "DB ALLARMI".ALL_SMS_MP;
      O     "DB ALLARMI".ALL_DMS_MP;
      O     "DB ALLARMI".ALL_SC_GPD;
      O     "DB ALLARMI".ALL_DC_GPD;
      O     "DB ALLARMI".ALL_SC_GND;
      O     "DB ALLARMI".ALL_DC_GND;
      O     "DB ALLARMI".ALL_SC_GPS;
      O     "DB ALLARMI".ALL_DC_GPS;
      O     "DB ALLARMI".ALL_SC_GNS;
      O     "DB ALLARMI".ALL_DC_GNS;
      O     "DB ALLARMI".ALL_SS_GPD;
      O     "DB ALLARMI".ALL_DS_GPD;
      O     "DB ALLARMI".ALL_SS_GPS;
      O     "DB ALLARMI".ALL_DS_GPS;
      O     "DB ALLARMI".ALL_SS_GND;
      O     "DB ALLARMI".ALL_DS_GND;
      O     "DB ALLARMI".ALL_SS_GNS;
      O     "DB ALLARMI".ALL_DS_GNS;
      O     "DB ALLARMI".ALL_SS_FP1;
      O     "DB ALLARMI".ALL_DS_FP1;
      O     "DB ALLARMI".ALL_SS_FP2;
      O     "DB ALLARMI".ALL_DS_FP2;
      O     "DB ALLARMI".ALL_STA1;
      O     "DB ALLARMI".ALL_DTA1;
      O     "DB ALLARMI".ALL_STA2;
      O     "DB ALLARMI".ALL_DTA2;
      O     "DB ALLARMI".ALL_RGPD;
      O     "DB ALLARMI".ALL_RGPS;
      O     "DB ALLARMI".ALL_RGND;
      O     "DB ALLARMI".ALL_RGNS;
      O     "DB ALLARMI".ALL_APR;
      O     "DB ALLARMI".ALL_CPR;
      O     "DB ALLARMI".ALL_RRV;
      O     "DB ALLARMI".ALL_RRO;
      O     "DB ALLARMI".ALL_APRB;
      O     "DB ALLARMI".ALL_CPRB;
      O     "DB ALLARMI".ALL_R0PRB;
      O     "DB ALLARMI".ALL_R180PRB;
      O     "DB ALLARMI".ALL_RPPRB;
      O     "DB ALLARMI".ALL_RDPRB;
      O     "DB ALLARMI".ALL_PPD;
      O     "DB ALLARMI".ALL_62;
      O     "DB ALLARMI".ALL_63;
      O     "DB ALLARMI".ALL_64;
      O     "DB ALLARMI".ALL_65;
      O     "DB ALLARMI".ALL_66;
      O     "DB ALLARMI".ALL_67;
      =     "BPA";

NETWORK
TITLE =BIT RICHIESTA SOSPENSIONE CICLO

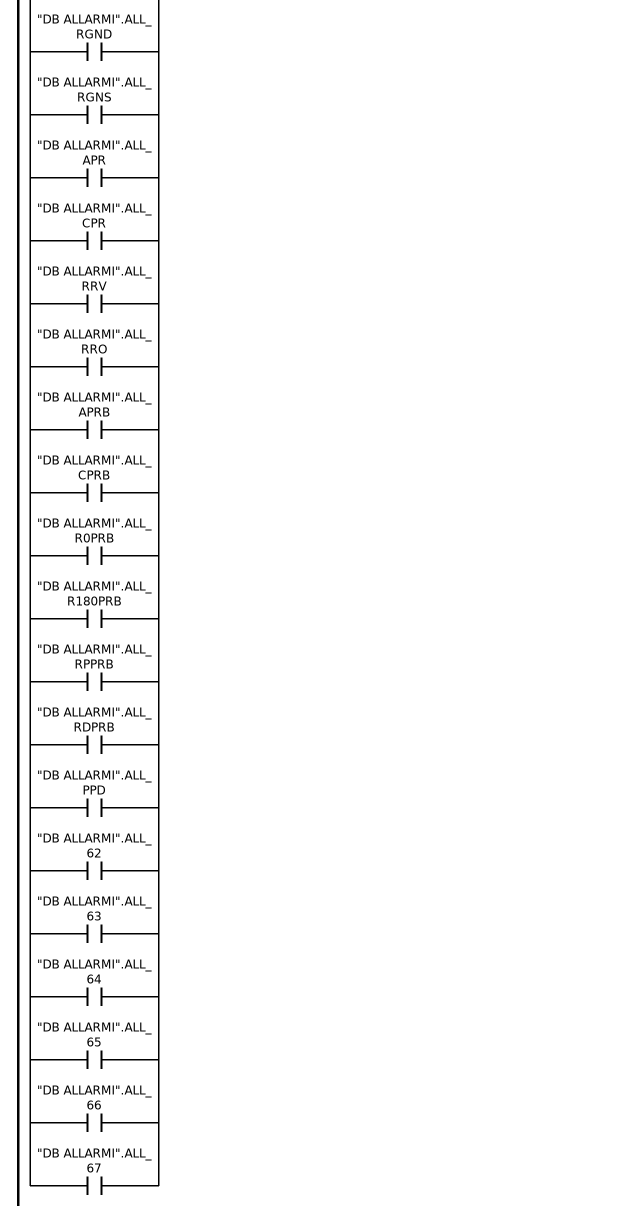
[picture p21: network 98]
      O     "DB ALLARMI".ALL_EM;
      O     "DB ALLARMI".ALL_CA;
      O     "DB ALLARMI".ALL_AI;
      O     "DB ALLARMI".ALL_AO;
      O     "DB ALLARMI".ALL_AZ;
      O     "DB ALLARMI".ALL_INV;
      O     "DB ALLARMI".ALL_ACI;
      O     "DB ALLARMI".ALL_AMS;
      O     "DB ALLARMI".ALL_AMGPD;
      O     "DB ALLARMI".ALL_AMGPS;
      O     "DB ALLARMI".ALL_AMGND;
      O     "DB ALLARMI".ALL_AMGNS;
      O     "DB ALLARMI".ALL_AMNF;
      O     "DB ALLARMI".ALL_SF;
      O     "DB ALLARMI".ALL_AAX;
      O     "DB ALLARMI".ALL_AAY;
      O     "DB ALLARMI".ALL_AAZ;
      O     "DB ALLARMI".ALL_AXIEN;
      O     "DB ALLARMI".ALL_AXIEP;
      O     "DB ALLARMI".ALL_AYIEN;
      O     "DB ALLARMI".ALL_AYIEP;
      O     "DB ALLARMI".ALL_AZIEN;
      O     "DB ALLARMI".ALL_AZIEP;
      O     "DB ALLARMI".ALL_PSCPDP;
      O     "DB ALLARMI".ALL_PSCPSP;
      O     "DB ALLARMI".ALL_PSCPRP;
      O     "DB ALLARMI".ALL_PND;
      O     "DB ALLARMI".ALL_SMD_MN;
      O     "DB ALLARMI".ALL_DMD_MN;
      O     "DB ALLARMI".ALL_SMS_MN;
      O     "DB ALLARMI".ALL_DMS_MN;
      O     "DB ALLARMI".ALL_MN_AD;
      O     "DB ALLARMI".ALL_MN_AS;
      O     "DB ALLARMI".ALL_MP_AD;
      O     "DB ALLARMI".ALL_MP_AS;
      O     "DB ALLARMI".ALL_SMD_MP;
      O     "DB ALLARMI".ALL_DMD_MP;
      O     "DB ALLARMI".ALL_SMS_MP;
      O     "DB ALLARMI".ALL_DMS_MP;
      O     "DB ALLARMI".ALL_SC_GPD;
      O     "DB ALLARMI".ALL_DC_GPD;
      O     "DB ALLARMI".ALL_SC_GND;
      O     "DB ALLARMI".ALL_DC_GND;
      O     "DB ALLARMI".ALL_SC_GPS;
      O     "DB ALLARMI".ALL_DC_GPS;
      O     "DB ALLARMI".ALL_SC_GNS;
      O     "DB ALLARMI".ALL_DC_GNS;
      O     "DB ALLARMI".ALL_SS_GPD;
      O     "DB ALLARMI".ALL_DS_GPD;
      O     "DB ALLARMI".ALL_SS_GPS;
      O     "DB ALLARMI".ALL_DS_GPS;
      O     "DB ALLARMI".ALL_SS_GND;
      O     "DB ALLARMI".ALL_DS_GND;
      O     "DB ALLARMI".ALL_SS_GNS;
      O     "DB ALLARMI".ALL_DS_GNS;
      O     "DB ALLARMI".ALL_SS_FP1;
      O     "DB ALLARMI".ALL_DS_FP1;
      O     "DB ALLARMI".ALL_SS_FP2;
      O     "DB ALLARMI".ALL_DS_FP2;
      O     "DB ALLARMI".ALL_STA1;
      O     "DB ALLARMI".ALL_DTA1;
      O     "DB ALLARMI".ALL_STA2;
      O     "DB ALLARMI".ALL_DTA2;
      O     "DB ALLARMI".ALL_RGPD;
      O     "DB ALLARMI".ALL_RGPS;
      O     "DB ALLARMI".ALL_RGND;
      O     "DB ALLARMI".ALL_RGNS;
      O     "DB ALLARMI".ALL_APR;
      O     "DB ALLARMI".ALL_CPR;
      O     "DB ALLARMI".ALL_RRV;
      O     "DB ALLARMI".ALL_RRO;
      O     "DB ALLARMI".ALL_APRB;
      O     "DB ALLARMI".ALL_CPRB;
      O     "DB ALLARMI".ALL_R0PRB;
      O     "DB ALLARMI".ALL_R180PRB;
      O     "DB ALLARMI".ALL_RPPRB;
      O     "DB ALLARMI".ALL_RDPRB;
      O     "DB ALLARMI".ALL_PPD;
      O     "DB ALLARMI".ALL_62;
      O     "DB ALLARMI".ALL_63;
      O     "DB ALLARMI".ALL_64;
      O     "DB ALLARMI".ALL_65;
      O     "DB ALLARMI".ALL_66;
      O     "DB ALLARMI".ALL_67;
      =     "BRSC";

NETWORK
TITLE =RESET ALARMI

      O     "PL.RA.PR";
      O     "PL.RA.PS";
      O     "PL.RA.PD";
      R     "DB ALLARMI".ALL_EM;
      R     "DB ALLARMI".ALL_CA;
      R     "DB ALLARMI".ALL_AA230V;
      R     "DB ALLARMI".ALL_IIA;
      R     "DB ALLARMI".ALL_AI;
      R     "DB ALLARMI".ALL_AO;
      R     "DB ALLARMI".ALL_AZ;
      R     "DB ALLARMI".ALL_INV;
      R     "DB ALLARMI".ALL_ACI;
      R     "DB ALLARMI".ALL_APV;
      R     "DB ALLARMI".ALL_AMS;
      R     "DB ALLARMI".ALL_AMGPD;
      R     "DB ALLARMI".ALL_AMGPS;
      R     "DB ALLARMI".ALL_AMGND;
      R     "DB ALLARMI".ALL_AMGNS;
      R     "DB ALLARMI".ALL_AMNF;
      R     "DB ALLARMI".ALL_AMCPS;
      R     "DB ALLARMI".ALL_AMCPD;
      R     "DB ALLARMI".ALL_AMCNS;
      R     "DB ALLARMI".ALL_AMCND;
      R     "DB ALLARMI".ALL_PAGPD;
      R     "DB ALLARMI".ALL_PAGPS;
      R     "DB ALLARMI".ALL_PAGND;
      R     "DB ALLARMI".ALL_PAGNS;
      R     "DB ALLARMI".ALL_SF;
      R     "DB ALLARMI".ALL_TRS;
      R     "DB ALLARMI".ALL_AAX;
      R     "DB ALLARMI".ALL_AAY;
      R     "DB ALLARMI".ALL_AAZ;
      R     "DB ALLARMI".ALL_AXIEN;
      R     "DB ALLARMI".ALL_AXIEP;
      R     "DB ALLARMI".ALL_AYIEN;
      R     "DB ALLARMI".ALL_AYIEP;
      R     "DB ALLARMI".ALL_AZIEN;
      R     "DB ALLARMI".ALL_AZIEP;
      R     "DB ALLARMI".ALL_PSCPDP;
      R     "DB ALLARMI".ALL_PSCPSP;
      R     "DB ALLARMI".ALL_PSCPRP;
      R     "DB ALLARMI".ALL_PND;
      R     "DB ALLARMI".ALL_SMD_MN;
      R     "DB ALLARMI".ALL_DMD_MN;
      R     "DB ALLARMI".ALL_SMS_MN;
      R     "DB ALLARMI".ALL_DMS_MN;
      R     "DB ALLARMI".ALL_MN_AD;
      R     "DB ALLARMI".ALL_MN_AS;
      R     "DB ALLARMI".ALL_MP_AD;
      R     "DB ALLARMI".ALL_MP_AS;
      R     "DB ALLARMI".ALL_SMD_MP;
      R     "DB ALLARMI".ALL_DMD_MP;
      R     "DB ALLARMI".ALL_SMS_MP;
      R     "DB ALLARMI".ALL_DMS_MP;
      R     "DB ALLARMI".ALL_SC_GPD;
      R     "DB ALLARMI".ALL_DC_GPD;
      R     "DB ALLARMI".ALL_SC_GND;
      R     "DB ALLARMI".ALL_DC_GND;
      R     "DB ALLARMI".ALL_SC_GPS;
      R     "DB ALLARMI".ALL_DC_GPS;
      R     "DB ALLARMI".ALL_SC_GNS;
      R     "DB ALLARMI".ALL_DC_GNS;
      R     "DB ALLARMI".ALL_SS_GPD;
      R     "DB ALLARMI".ALL_DS_GPD;
      R     "DB ALLARMI".ALL_SS_GPS;
      R     "DB ALLARMI".ALL_DS_GPS;
      R     "DB ALLARMI".ALL_SS_GND;
      R     "DB ALLARMI".ALL_DS_GND;
      R     "DB ALLARMI".ALL_SS_GNS;
      R     "DB ALLARMI".ALL_DS_GNS;
      R     "DB ALLARMI".ALL_SS_FP1;
      R     "DB ALLARMI".ALL_DS_FP1;
      R     "DB ALLARMI".ALL_SS_FP2;
      R     "DB ALLARMI".ALL_DS_FP2;
      R     "DB ALLARMI".ALL_STA1;
      R     "DB ALLARMI".ALL_DTA1;
      R     "DB ALLARMI".ALL_STA2;
      R     "DB ALLARMI".ALL_DTA2;
      R     "DB ALLARMI".ALL_RGPD;
      R     "DB ALLARMI".ALL_RGPS;
      R     "DB ALLARMI".ALL_RGND;
      R     "DB ALLARMI".ALL_RGNS;
      R     "DB ALLARMI".ALL_APR;
      R     "DB ALLARMI".ALL_CPR;
      R     "DB ALLARMI".ALL_RRV;
      R     "DB ALLARMI".ALL_RRO;
      R     "DB ALLARMI".ALL_APRB;
      R     "DB ALLARMI".ALL_CPRB;
      R     "DB ALLARMI".ALL_R0PRB;
      R     "DB ALLARMI".ALL_R180PRB;
      R     "DB ALLARMI".ALL_RPPRB;
      R     "DB ALLARMI".ALL_RDPRB;
      R     "DB ALLARMI".ALL_PPD;
      R     "DB ALLARMI".ALL_62;
      R     "DB ALLARMI".ALL_63;
      R     "DB ALLARMI".ALL_64;
      R     "DB ALLARMI".ALL_65;
      R     "DB ALLARMI".ALL_66;
      R     "DB ALLARMI".ALL_67;

NETWORK
TITLE =GESTIONE ACQUISIZIONE ALLARMI PER OP17

      L     DB118.DBW    0;
      INVI  ;
      T     DB118.DBW   16;
//------
      L     DB118.DBW    2;
      INVI  ;
      T     DB118.DBW   18;
//------
      L     DB118.DBW    4;
      INVI  ;
      T     DB118.DBW   20;
//------
      L     DB118.DBW    6;
      INVI  ;
      T     DB118.DBW   22;
//------
      L     DB118.DBW    8;
      INVI  ;
      T     DB118.DBW   24;
//------
      L     DB118.DBW   10;
      INVI  ;
      T     DB118.DBW   26;
//------
      L     DB118.DBW   12;
      INVI  ;
      T     DB118.DBW   28;
//------
      L     DB118.DBW   14;
      INVI  ;
      T     DB118.DBW   30;

END_FUNCTION

